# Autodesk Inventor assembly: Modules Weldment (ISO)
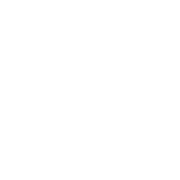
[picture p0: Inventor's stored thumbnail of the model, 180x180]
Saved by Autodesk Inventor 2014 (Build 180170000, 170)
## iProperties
Created: 2013-05
Part Number: Modules Weldment (ISO)
Document SubType Name: Weldment
Designer: Wally
Weld Material: Welded Aluminum-6061
Author: Wally
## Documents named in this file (1)
- C:\CAD Courses\Inventor\Templates\Metric Templates\Modules Weldment (ISO).iam
